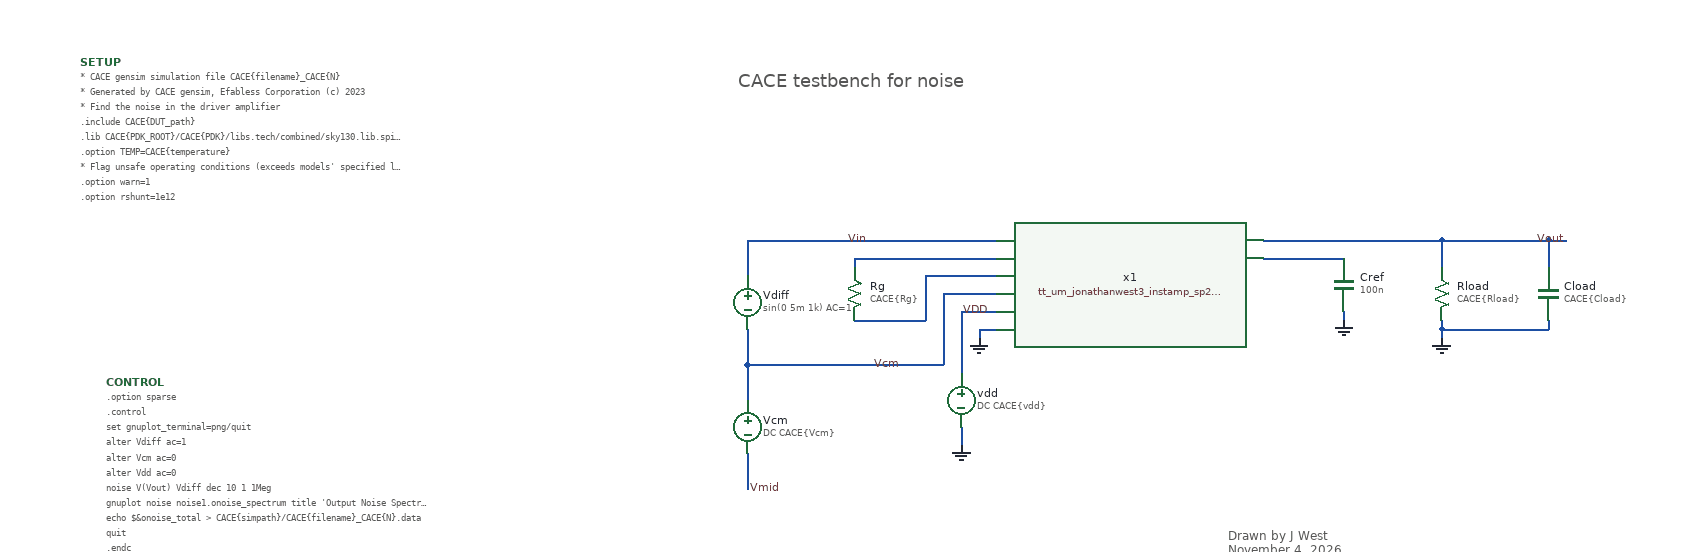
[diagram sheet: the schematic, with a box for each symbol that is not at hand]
v {xschem version=3.4.8RC file_version=1.3}
G {}
K {}
V {}
S {}
F {}
E {}
T {CACE testbench for noise} 810 -690 0 0 0.6 0.6 {}
T {Drawn by J West
November 4, 2026
Revision 0
} 1360 -180 0 0 0.4 0.4 {}
N 1720 -500 1740 -500 {
lab=Vout}
N 940 -480 940 -470 {lab=#net1}
N 940 -480 1100 -480 {lab=#net1}
N 940 -410 1020 -410 {lab=#net2}
N 1020 -440 1020 -410 {lab=#net2}
N 1040 -420 1040 -360 {lab=Vcm}
N 820 -360 1040 -360 {lab=Vcm}
N 1400 -480 1490 -480 {lab=#net3}
N 1490 -420 1490 -410 {lab=GND}
N 1060 -290 1060 -270 {lab=GND}
N 1060 -370 1060 -350 {lab=VDD}
N 820 -260 820 -250 {lab=Vmid}
N 820 -500 1100 -500 {lab=Vin}
N 1060 -420 1100 -420 {lab=VDD}
N 1600 -400 1600 -390 {lab=GND}
N 1600 -410 1600 -400 {lab=GND}
N 1650 -400 1720 -400 {lab=GND}
N 1720 -410 1720 -400 {lab=GND}
N 1720 -500 1720 -470 {lab=Vout}
N 1600 -500 1600 -470 {lab=Vout}
N 820 -500 820 -460 {lab=Vin}
N 820 -400 820 -360 {lab=Vcm}
N 820 -360 820 -320 {lab=Vcm}
N 1650 -500 1720 -500 {
lab=Vout}
N 1400 -500 1600 -500 {
lab=Vout}
N 1060 -420 1060 -370 {lab=VDD}
N 1600 -500 1650 -500 {lab=Vout}
N 1600 -400 1650 -400 {lab=GND}
N 820 -250 820 -220 {lab=Vmid}
N 1020 -460 1020 -440 {lab=#net2}
N 1020 -460 1100 -460 {lab=#net2}
N 1040 -440 1040 -420 {lab=Vcm}
N 1040 -440 1100 -440 {lab=Vcm}
N 1080 -400 1080 -390 {lab=GND}
N 1080 -400 1100 -400 {lab=GND}
C {devices/code_shown.sym} 100 -340 0 0 {name=CONTROL only_toplevel=false value="
.option sparse
.control
set gnuplot_terminal=png/quit
alter Vdiff ac=1
alter Vcm ac=0
alter Vdd ac=0
noise V(Vout) Vdiff dec 10 1 1Meg

gnuplot noise noise1.onoise_spectrum  title 'Output Noise Spectrum'  xlabel 'Freq' ylabel 'Noise V/root(Hz)'

echo $&onoise_total > CACE\{simpath\}/CACE\{filename\}_CACE\{N\}.data

quit
.endc
"}
C {devices/code_shown.sym} 70 -700 0 0 {name=SETUP only_toplevel=false value="* CACE gensim simulation file CACE\{filename\}_CACE\{N\}
* Generated by CACE gensim, Efabless Corporation (c) 2023
* Find the noise in the driver amplifier

.include CACE\{DUT_path\}

.lib CACE\{PDK_ROOT\}/CACE\{PDK\}/libs.tech/combined/sky130.lib.spice CACE\{corner\}

.option TEMP=CACE\{temperature\}
* Flag unsafe operating conditions (exceeds models' specified limits)
.option warn=1
.option rshunt=1e12
"}
C {devices/vsource.sym} 820 -290 0 0 {name=Vcm value="DC CACE\{Vcm\}" savecurrent=false}
C {devices/lab_wire.sym} 1740 -500 0 0 {name=p25 sig_type=std_logic lab=Vout}
C {devices/vsource.sym} 1060 -320 0 0 {name=vdd value="DC CACE\{vdd\}" savecurrent=false}
C {devices/lab_wire.sym} 960 -360 0 1 {name=p4 sig_type=std_logic lab=Vcm}
C {devices/res.sym} 940 -440 0 0 {name=Rg
value=CACE\{Rg\}
device=resistor}
C {capa.sym} 1490 -450 0 0 {name=Cref
m=1
value=100n
footprint=1206
device="ceramic capacitor"}
C {devices/gnd.sym} 1490 -410 0 0 {name=l2 lab=GND}
C {devices/gnd.sym} 1060 -270 0 0 {name=l1 lab=GND}
C {devices/gnd.sym} 1080 -390 0 0 {name=l5 lab=GND}
C {devices/lab_wire.sym} 1060 -420 0 1 {name=p5 sig_type=std_logic lab=VDD}
C {devices/lab_wire.sym} 930 -500 0 1 {name=p6 sig_type=std_logic lab=Vin}
C {devices/res.sym} 1600 -440 0 0 {name=Rload
value=CACE\{Rload\}
device=resistor}
C {capa.sym} 1720 -440 0 0 {name=Cload
m=1
value=CACE\{Cload\}
footprint=1206
device="ceramic capacitor"}
C {devices/gnd.sym} 1600 -390 0 0 {name=l3 lab=GND}
C {vsource.sym} 820 -430 0 0 {name=Vdiff value="sin(0 5m 1k) AC=1"}
C {devices/lab_wire.sym} 820 -220 0 1 {name=p2 sig_type=std_logic lab=Vmid}
C {tt_um_jonathanwest3_instamp_sp2026.sym} 1250 -250 0 0 {name=x1}
